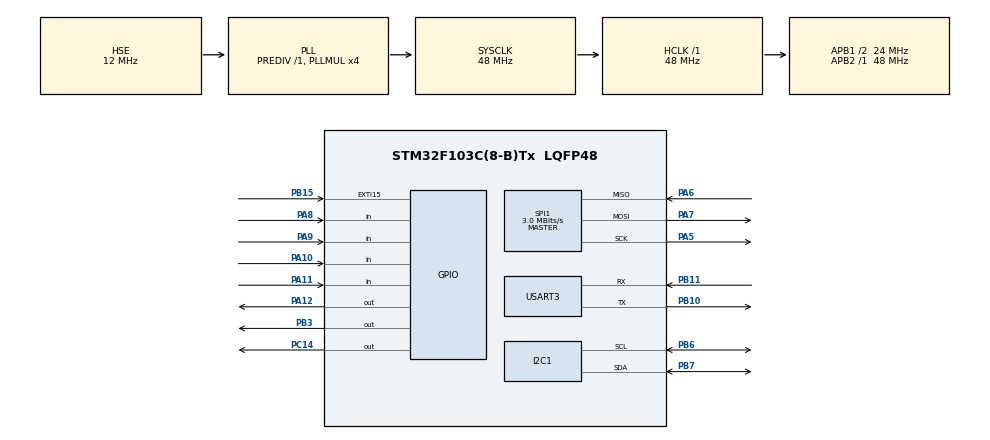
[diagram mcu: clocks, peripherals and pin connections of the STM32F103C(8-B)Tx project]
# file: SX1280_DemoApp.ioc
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I2C1.I2C_Mode=I2C_Standard
Mcu.Family=STM32F1
Mcu.Name=STM32F103C(8-B)Tx
Mcu.Package=LQFP48
NVIC.EXTI15_10_IRQn=true\:0\:0\:false\:false\:true\:true\:true\:true
NVIC.PriorityGroup=NVIC_PRIORITYGROUP_4
NVIC.USART3_IRQn=true\:0\:0\:false\:false\:true\:true\:true\:true
PA10.Signal=GPIO_Input
PA11.Signal=GPIO_Input
PA12.GPIO_PuPd=GPIO_PULLDOWN
PA12.GPIO_Speed=GPIO_SPEED_FREQ_HIGH
PA12.Signal=GPIO_Output
PA13.Mode=Serial_Wire
PA13.Signal=SYS_JTMS-SWDIO
PA14.Mode=Serial_Wire
PA14.Signal=SYS_JTCK-SWCLK
PA5.Mode=Full_Duplex_Master
PA5.Signal=SPI1_SCK
PA6.Mode=Full_Duplex_Master
PA6.Signal=SPI1_MISO
PA7.Mode=Full_Duplex_Master
PA7.Signal=SPI1_MOSI
PA8.GPIO_PuPd=GPIO_PULLDOWN
PA8.Signal=GPIO_Input
PA9.Signal=GPIO_Input
PB10.Mode=Asynchronous
PB10.Signal=USART3_TX
PB11.Mode=Asynchronous
PB11.Signal=USART3_RX
PB15.Signal=GPXTI15
PB3.PinState=GPIO_PIN_SET
PB3.Signal=GPIO_Output
PB6.Mode=I2C
PB6.Signal=I2C1_SCL
PB7.Mode=I2C
PB7.Signal=I2C1_SDA
PC14-OSC32_IN.Signal=GPIO_Output
PD0-OSC_IN.Mode=HSE-External-Oscillator
PD0-OSC_IN.Signal=RCC_OSC_IN
PD1-OSC_OUT.Mode=HSE-External-Oscillator
PD1-OSC_OUT.Signal=RCC_OSC_OUT
ProjectManager.HeapSize=0x200
ProjectManager.StackSize=0x400
ProjectManager.TargetToolchain=MDK-ARM V5
RCC.AHBFreq_Value=48000000
RCC.APB1CLKDivider=RCC_HCLK_DIV2
RCC.APB1Freq_Value=24000000
RCC.APB1TimFreq_Value=48000000
RCC.APB2Freq_Value=48000000
RCC.APB2TimFreq_Value=48000000
RCC.HCLKFreq_Value=48000000
RCC.HSE_VALUE=12000000
RCC.PLLMUL=RCC_PLL_MUL4
RCC.PLLSourceVirtual=RCC_PLLSOURCE_HSE
RCC.SYSCLKFreq_VALUE=48000000
RCC.SYSCLKSource=RCC_SYSCLKSOURCE_PLLCLK
RCC.USBFreq_Value=48000000
SPI1.BaudRatePrescaler=SPI_BAUDRATEPRESCALER_16
SPI1.CalculateBaudRate=3.0 MBits/s
SPI1.Direction=SPI_DIRECTION_2LINES
SPI1.Mode=SPI_MODE_MASTER
SPI1.VirtualType=VM_MASTER
USART3.VirtualMode=VM_ASYNC
board=custom

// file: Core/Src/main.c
/* USER CODE BEGIN Header */
/**
  ******************************************************************************
  * @file           : main.c
  * @brief          : Main program body
  ******************************************************************************
  * @attention
  *
  * Copyright (c) 2024 STMicroelectronics.
  * All rights reserved.
  *
  * This software is licensed under terms that can be found in the LICENSE file
  * in the root directory of this software component.
  * If no LICENSE file comes with this software, it is provided AS-IS.
  *
  ******************************************************************************
  */
/* USER CODE END Header */
#include "main.h"

/* USER CODE BEGIN Includes */
#include <stdio.h>
#include "boards.h"
#include "main_ranging.h"
#include "SEGGER_RTT.h"
/* USER CODE END Includes */

I2C_HandleTypeDef hi2c1;

SPI_HandleTypeDef hspi1;

UART_HandleTypeDef huart3;

void SystemClock_Config(void);
static void MX_GPIO_Init(void);
static void MX_I2C1_Init(void);
static void MX_SPI1_Init(void);
static void MX_USART3_UART_Init(void);

int main(void)
{

  /* MCU Configuration--------------------------------------------------------*/

  /* Reset of all peripherals, Initializes the Flash interface and the Systick. */
  HAL_Init();

  /* Configure the system clock */
  SystemClock_Config();

  /* Initialize all configured peripherals */
  MX_GPIO_Init();
  MX_I2C1_Init();
  MX_SPI1_Init();
  MX_USART3_UART_Init();
  /* USER CODE BEGIN 2 */
  SEGGER_RTT_Init();
  /* USER CODE END 2 */

  /* Infinite loop */
  /* USER CODE BEGIN WHILE */
  // while (1)
  {
    /* USER CODE END WHILE */
    main_ranging();

    #if 0

    HAL_Delay(2000);
    printf("start timer!\n");
    TimerCreateTimer(tttt, (void *)val++, 1000);

    uint8_t data[5] = {0x01, 0x02, 0x03, 0x04, 0x05};
    HAL_GPIO_WritePin(RADIO_NSS_PORT, RADIO_NSS_PIN, GPIO_PIN_SET);
    HAL_SPI_Transmit(&hspi1, data, 5, 1000);
    HAL_GPIO_WritePin(RADIO_NSS_PORT, RADIO_NSS_PIN, GPIO_PIN_RESET);

    GPIO_PinState tmp = HAL_GPIO_ReadPin(RADIO_BUSY_PORT, RADIO_BUSY_PIN);
    if (val != (uint32_t)tmp) {
      val = (uint32_t)tmp;
      SEGGER_RTT_printf(0, "RADIO_BUSY_PIN: %d\n", val);
    }

    // 测试串口3发送数据
    HAL_Delay(1000);
    uint8_t data[5] = {'H', 'e', 'l', 'l', 'o'};
    HAL_UART_Transmit(&huart3, data, 5, 1000);
    #endif

  }
}

void SystemClock_Config(void)
{
  RCC_OscInitTypeDef RCC_OscInitStruct = {0};
  RCC_ClkInitTypeDef RCC_ClkInitStruct = {0};

  /** Initializes the RCC Oscillators according to the specified parameters
  * in the RCC_OscInitTypeDef structure.
  */
  RCC_OscInitStruct.OscillatorType = RCC_OSCILLATORTYPE_HSE;
  RCC_OscInitStruct.HSEState = RCC_HSE_ON;
  RCC_OscInitStruct.HSEPredivValue = RCC_HSE_PREDIV_DIV1;
  RCC_OscInitStruct.HSIState = RCC_HSI_ON;
  RCC_OscInitStruct.PLL.PLLState = RCC_PLL_ON;
  RCC_OscInitStruct.PLL.PLLSource = RCC_PLLSOURCE_HSE;
  RCC_OscInitStruct.PLL.PLLMUL = RCC_PLL_MUL4;
  if (HAL_RCC_OscConfig(&RCC_OscInitStruct) != HAL_OK)
  {
    Error_Handler();
  }

  /** Initializes the CPU, AHB and APB buses clocks
  */
  RCC_ClkInitStruct.ClockType = RCC_CLOCKTYPE_HCLK|RCC_CLOCKTYPE_SYSCLK
                              |RCC_CLOCKTYPE_PCLK1|RCC_CLOCKTYPE_PCLK2;
  RCC_ClkInitStruct.SYSCLKSource = RCC_SYSCLKSOURCE_PLLCLK;
  RCC_ClkInitStruct.AHBCLKDivider = RCC_SYSCLK_DIV1;
  RCC_ClkInitStruct.APB1CLKDivider = RCC_HCLK_DIV2;
  RCC_ClkInitStruct.APB2CLKDivider = RCC_HCLK_DIV1;

  if (HAL_RCC_ClockConfig(&RCC_ClkInitStruct, FLASH_LATENCY_1) != HAL_OK)
  {
    Error_Handler();
  }
}

static void MX_I2C1_Init(void)
{

  hi2c1.Instance = I2C1;
  hi2c1.Init.ClockSpeed = 100000;
  hi2c1.Init.DutyCycle = I2C_DUTYCYCLE_2;
  hi2c1.Init.OwnAddress1 = 0;
  hi2c1.Init.AddressingMode = I2C_ADDRESSINGMODE_7BIT;
  hi2c1.Init.DualAddressMode = I2C_DUALADDRESS_DISABLE;
  hi2c1.Init.OwnAddress2 = 0;
  hi2c1.Init.GeneralCallMode = I2C_GENERALCALL_DISABLE;
  hi2c1.Init.NoStretchMode = I2C_NOSTRETCH_DISABLE;
  if (HAL_I2C_Init(&hi2c1) != HAL_OK)
  {
    Error_Handler();
  }

}

static void MX_SPI1_Init(void)
{

  /* SPI1 parameter configuration*/
  #if 0
  hspi1.Instance = SPI1;
  hspi1.Init.Mode = SPI_MODE_MASTER;
  hspi1.Init.Direction = SPI_DIRECTION_2LINES;
  hspi1.Init.DataSize = SPI_DATASIZE_8BIT;
  hspi1.Init.CLKPolarity = SPI_POLARITY_LOW;
  hspi1.Init.CLKPhase = SPI_PHASE_1EDGE;
  hspi1.Init.NSS = SPI_NSS_SOFT;
  hspi1.Init.BaudRatePrescaler = SPI_BAUDRATEPRESCALER_16;
  hspi1.Init.FirstBit = SPI_FIRSTBIT_MSB;
  hspi1.Init.TIMode = SPI_TIMODE_DISABLE;
  hspi1.Init.CRCCalculation = SPI_CRCCALCULATION_DISABLE;
  hspi1.Init.CRCPolynomial = 10;
  if (HAL_SPI_Init(&hspi1) != HAL_OK)
  {
    Error_Handler();
  }
  #endif
  /* USER CODE BEGIN SPI1_Init 2 */
  SpiInit();
  /* USER CODE END SPI1_Init 2 */

};

static void MX_USART3_UART_Init(void)
{

  huart3.Instance = USART3;
  huart3.Init.BaudRate = 115200;
  huart3.Init.WordLength = UART_WORDLENGTH_8B;
  huart3.Init.StopBits = UART_STOPBITS_1;
  huart3.Init.Parity = UART_PARITY_NONE;
  huart3.Init.Mode = UART_MODE_TX_RX;
  huart3.Init.HwFlowCtl = UART_HWCONTROL_NONE;
  huart3.Init.OverSampling = UART_OVERSAMPLING_16;
  if (HAL_UART_Init(&huart3) != HAL_OK)
  {
    Error_Handler();
  }

}

static void MX_GPIO_Init(void)
{
  GPIO_InitTypeDef GPIO_InitStruct = {0};

  /* GPIO Ports Clock Enable */
  __HAL_RCC_GPIOC_CLK_ENABLE();
  __HAL_RCC_GPIOD_CLK_ENABLE();
  __HAL_RCC_GPIOA_CLK_ENABLE();
  __HAL_RCC_GPIOB_CLK_ENABLE();

  /*Configure GPIO pin Output Level */
  HAL_GPIO_WritePin(GPIOC, GPIO_PIN_14, GPIO_PIN_RESET);

  /*Configure GPIO pin Output Level */
  HAL_GPIO_WritePin(GPIOA, GPIO_PIN_12, GPIO_PIN_RESET);

  /*Configure GPIO pin Output Level */
  HAL_GPIO_WritePin(GPIOB, GPIO_PIN_3, GPIO_PIN_SET);

  /*Configure LED GREEN GPIO pin Output Level */
  HAL_GPIO_WritePin(GPIOB, GPIO_PIN_8, GPIO_PIN_SET);
    /*Configure LED RED GPIO pin Output Level */
  HAL_GPIO_WritePin(GPIOB, GPIO_PIN_9, GPIO_PIN_SET);

  /*Configure GPIO pin : PC14 */
  GPIO_InitStruct.Pin = GPIO_PIN_14;
  GPIO_InitStruct.Mode = GPIO_MODE_OUTPUT_PP;
  GPIO_InitStruct.Pull = GPIO_NOPULL;
  GPIO_InitStruct.Speed = GPIO_SPEED_FREQ_LOW;
  HAL_GPIO_Init(GPIOC, &GPIO_InitStruct);

  /*Configure GPIO pin : PB8=LED_G, PB9=LED_R */
  GPIO_InitStruct.Pin = GPIO_PIN_8 | GPIO_PIN_9;
  GPIO_InitStruct.Mode = GPIO_MODE_OUTPUT_PP;
  GPIO_InitStruct.Pull = GPIO_NOPULL;
  GPIO_InitStruct.Speed = GPIO_SPEED_FREQ_LOW;
  HAL_GPIO_Init(GPIOB, &GPIO_InitStruct);

  /*Configure GPIO pin : PB15 */
  GPIO_InitStruct.Pin = GPIO_PIN_15;
  GPIO_InitStruct.Mode = GPIO_MODE_IT_RISING;
  GPIO_InitStruct.Pull = GPIO_PULLDOWN;
  HAL_GPIO_Init(GPIOB, &GPIO_InitStruct);

  /*Configure GPIO pin : PA8 */
  GPIO_InitStruct.Pin = GPIO_PIN_8;
  GPIO_InitStruct.Mode = GPIO_MODE_INPUT;
  GPIO_InitStruct.Pull = GPIO_PULLDOWN;
  HAL_GPIO_Init(GPIOA, &GPIO_InitStruct);

  /*Configure GPIO pin : PA15,PB0， KEY INPUT */
  GPIO_InitStruct.Pin = GPIO_PIN_15;
  GPIO_InitStruct.Mode = GPIO_MODE_INPUT;
  GPIO_InitStruct.Pull = GPIO_PULLUP;
  HAL_GPIO_Init(GPIOA, &GPIO_InitStruct);

  GPIO_InitStruct.Pin = GPIO_PIN_0;
  GPIO_InitStruct.Mode = GPIO_MODE_INPUT;
  GPIO_InitStruct.Pull = GPIO_PULLUP;
  HAL_GPIO_Init(GPIOB, &GPIO_InitStruct);

  /*Configure GPIO pins : PA9 PA10 PA11 */
  GPIO_InitStruct.Pin = GPIO_PIN_9|GPIO_PIN_10|GPIO_PIN_11;
  GPIO_InitStruct.Mode = GPIO_MODE_INPUT;
  GPIO_InitStruct.Pull = GPIO_NOPULL;
  HAL_GPIO_Init(GPIOA, &GPIO_InitStruct);

  /*Configure GPIO pin : PA12 */
  GPIO_InitStruct.Pin = GPIO_PIN_12;
  GPIO_InitStruct.Mode = GPIO_MODE_OUTPUT_PP;
  GPIO_InitStruct.Pull = GPIO_PULLDOWN;
  GPIO_InitStruct.Speed = GPIO_SPEED_FREQ_LOW;
  HAL_GPIO_Init(GPIOA, &GPIO_InitStruct);

  /*Configure GPIO pin : PB3 */
  GPIO_InitStruct.Pin = GPIO_PIN_3;
  GPIO_InitStruct.Mode = GPIO_MODE_OUTPUT_PP;
  GPIO_InitStruct.Pull = GPIO_NOPULL;
  GPIO_InitStruct.Speed = GPIO_SPEED_FREQ_LOW;
  HAL_GPIO_Init(GPIOB, &GPIO_InitStruct);

  /* EXTI interrupt init*/
  HAL_NVIC_SetPriority(EXTI15_10_IRQn, 0, 0);
  HAL_NVIC_EnableIRQ(EXTI15_10_IRQn);

}

void Error_Handler(void)
{
  __disable_irq();
  while (1)
  {
  }
}
